! (c) 2009  Infineon Technologies AG, Munich
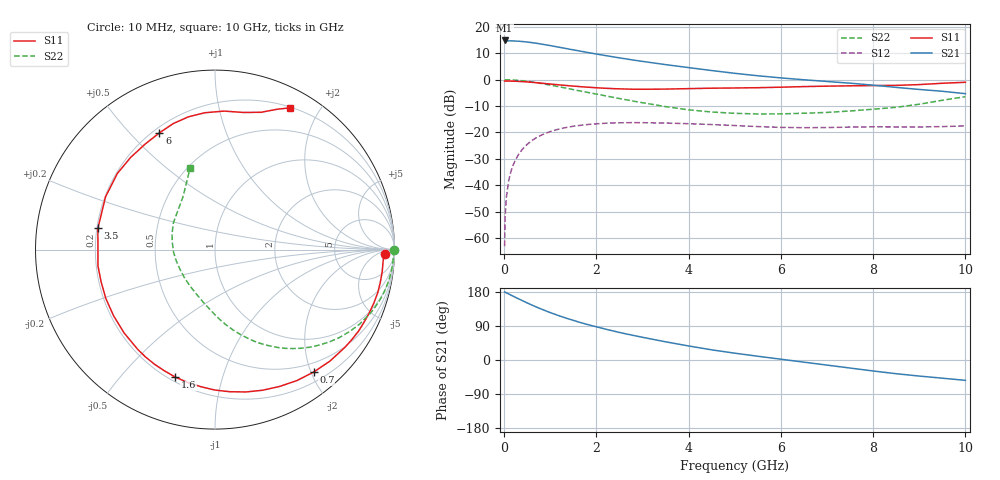
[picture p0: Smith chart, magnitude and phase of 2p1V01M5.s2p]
! Infineon Technologies  Discrete & RF Semiconductors
! BFP420
! VCE =  1.0 V,  IC =  1.5 mA
! Common Emitter S-Parameters:  Nov 2009
# GHz  S  MA  R  50
!  f  S11  S21  S12  S22
! GHz  MAG  ANG  MAG  ANG  MAG  ANG  MAG  ANG
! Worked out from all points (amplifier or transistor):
!   46 points, 10 MHz to 10 GHz, reference 50 ohm
!   highest |S21| = 14.9 dB at 10 MHz (marker M1)
!   |S21| within 3 dB of that: start of sweep to 1.324 GHz
!   unconditionally stable (mu >= 1): 4.133 GHz to end of sweep
!   at 300 MHz: K = 0.04, MSG = 21.6 dB, |S12| = -28.7 dB
!   at 1.7 GHz: K = 0.34, MSG = 13.9 dB, |S12| = -17.2 dB
!   at 10 GHz: K = 1.25, MAG = 3.1 dB, |S12| = -17.5 dB
!   lowest NFmin = 0.52 dB at 900 MHz
!   S11 on the Smith chart (normalised r, x): 10 MHz: 29, -14; 700 MHz: 0.35, -2.04; 1.6 GHz: 0.22, -0.71; 3.5 GHz: 0.20, +0.09; 6 GHz: 0.22, +0.61; 10 GHz: 0.21, +1.64
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0.01  0.9451 -1.5  5.537 179.4  0.0007 82.0  0.9946 -0.1
0.02  0.9427 -1.6  5.374 179.2  0.0025 89.7  0.9947 -0.9
0.05  0.939 -3.7  5.409 177.1  0.0061 88.1  0.9946 -2.3
0.1  0.9397 -7.5  5.445 174.2  0.0124 85.7  0.9928 -4.7
0.15  0.9389 -11.1  5.441 171.1  0.0186 83.6  0.9895 -7.1
0.3  0.9292 -22.3  5.365 162.2  0.0367 76.6  0.9713 -14.1
0.45  0.9126 -33.3  5.227 153.5  0.054 69.9  0.9427 -20.9
0.7  0.8762 -51.2  4.901 139.7  0.0796 59.2  0.8783 -31.3
0.9  0.8432 -64.7  4.581 129.8  0.0965 51.5  0.8195 -38.8
1.1  0.8117 -77.7  4.262 120.7  0.1106 44.5  0.7601 -45.6
1.4  0.7678 -96.0  3.809 108.3  0.1267 35.0  0.6748 -54.6
1.6  0.7441 -107.3  3.538 100.8  0.1346 29.6  0.623 -59.8
1.7  0.7316 -112.7  3.415 97.3  0.1382 27.0  0.5991 -62.3
2.2  0.6871 -137.5  2.86 81.4  0.1494 15.6  0.4935 -73.4
2.6  0.6665 -155.9  2.509 70.0  0.153 7.7  0.4231 -81.7
3.5  0.6631 169.7  1.929 48.0  0.1506 -5.8  0.3086 -100.6
4.5  0.6898 142.1  1.49 26.8  0.1412 -15.8  0.244 -125.9
5.5  0.7047 123.7  1.186 9.9  0.1292 -21.0  0.2239 -150.7
6  0.7203 115.5  1.081 2.1  0.1247 -21.9  0.2248 -163.8
7  0.7545 101.3  0.924 -13.5  0.1239 -22.6  0.2396 171.8
8.5  0.7803 78.3  0.714 -36.2  0.1274 -27.4  0.2996 133.8
10  0.8926 62.2  0.543 -53.7  0.1332 -29.2  0.4767 106.9
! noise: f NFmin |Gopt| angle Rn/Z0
0.9  0.52  0.55  33  0.27
1.8  1.07  0.35  77  0.21
2.4  1.18  0.36  101  0.18
3  1.41  0.36  134  0.13
4  1.68  0.4  -172  0.1
5  2.08  0.44  -130  0.32
6  2.89  0.57  -114  0.39
